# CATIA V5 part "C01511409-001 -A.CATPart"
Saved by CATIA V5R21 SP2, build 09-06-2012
Part number: C01511409-001
Revision: ---
Description: PROPRIETARY NOTICE (do not delete / modify)  ***************************************************************************************************  LA SOCIETE EN COMMANDITE  AIRBUS CANADA  ("AIRBUS CANADA")  PAR  L'INTERMEDIAIRE  DE  SES  DIVISIONS  ET/OU  FILIALES  CORPORATIVES,  FOURNIT  LES PRESENTES  INFORMATIONS  AU  GOUVERNEMENT  A  TITRE CONFIDENTIEL. CES  INFORMATIONS ONT UNE TENEUR CONFIDENTIELLE,  AVEC DROITS DE PROPRIETE,  ET NOUS LES CONSIDERONS  EXCLUS  DE   L'APPLICATION  DE  LA LOI SUR L'ACCES A L'INFORMATION  (CANADA),  LES  LOIS  SUR  L'ACCES  A  L'INFORMATION  EUROPEENNES,  LE FREEDOM OF INFORMATION ACT (ETATS-UNIS) ET D'AUTRES LOIS SEMBLABLES. ELLES  PEUVENT  AUSSI  CONSTITUER DES SECRETS INDUSTRIELS DE NOTRE SOCIETE OU DE TIERCES PARTIES. LA DIVULGATION  PUBLIQUE  DE CES  INFORMATIONS NUIRAIT A AIRBUS CANADA OU A DES TIERCES PARTIES.  CES INFORMATIONS PEUVENT EGALEMENT CONTENIR  DES DONNEES QUI SONT CONTROLEE PAR DES LOIS DE CONTROLE DES EXPORTATIONS DU CANADA, L’EUROPE OU LES  ETATS-  UNIS. TOUTE EXPORTATION OU REEXPORTATION DE DONNEES CONTROLEES SANS AUTORISATION EST STRICTEMENT INTERDITE.  TOUTE INTENTION DE LES DIVULGUER EN TOUT OU EN PARTIE DEVRA ETRE SIGNIFIEE A L'AVANCE ET PAR ECRIT AU VICE-  PRESIDENT, SERVICES JURIDIQUES ET CONFORMITE ET SECRETAIRE CORPORATIF D'AIRBUS CANADA.    AIRBUS CANADA LIMITED PARTNERSHIP  ("AIRBUS CANADA"),  BY ITS AFFILIATES AND/OR SUBSIDIARIES, PROVIDES THIS  INFORMATION TO THE GOVERNMENT IN CONFIDENCE. THIS IS PROPRIETARY CONFIDENTIAL INFORMATION WHICH WE CONSIDER  EXCLUDED  FROM  THE  APPLICATION OF THE ACCESS TO INFORMATION ACT (CANADA),  THE FREEDOM OF INFORMATION ACT  (U.S.A.),  THE ACCESS TO INFORMATION LAWS IN EUROPE, AND OTHER SIMILAR LEGISLATION. AND MAY ALSO CONSTITUTE  TRADE SECRETS OF OUR  COMPANY OR THIRD PARTIES.  PUBLIC  RELEASE  OF  THIS INFORMATION  WOULD BE HARMFUL TO  AIRBUS CANADA OR THIRD PARTIES.  THIS  INFORMATION  MAY  ALSO  CONTAIN DATA THAT IS CONTROLLED BY CANADIAN,  EUROPEAN, OR U.S.A. EXPORT CONTROL LAWS. ANY UNAUTHORIZED EXPORT OR RE-EXPORT OF ANY EXPORT CONTROLLED DATA  IS STRICTLY PROHIBITED  ANY INTENTION TO DISCLOSE SUCH INFORMATION,  OR  PART THEREOF,  MUST BE NOTIFIED IN  ADVANCE AND IN WRITING TO THE VICE PRESIDENT, LEGAL AND COMPLIANCE AND CORPORATE SECRETARY OF AIRBUS CANADA.        LES RENSEIGNEMENTS,  LES DONNEES  ET  DESSINS  TECHNIQUES  DIVULGUES  DANS  LES PRESENTES SONT LA PROPRIETE  EXCLUSIVE DE LA SOCIETE EN COMMANDITE AIRBUS CANADA ("AIRBUS CANADA") OU COMPORTENT DES DROITS DE PROPRIETE  APPARTENANT  A  AUTRUI ET NE PEUVENT ETRE DIVULGUES  A  QUICONQUE  NI  UTILISES PAR QUI QUE CE SOIT SANS LE  CONSENTEMENT  ECRIT  D’AIRBUS  CANADA.  LE DETENTEUR DES  PRESENTES  S'ENGAGE, DANS TOUTES CIRCONSTANCES, A  GARDER CONFIDENTIELS LES DONNEES ET DESSINS TECHNIQUES QU'ELLES CONTIENNENT.   CE QUI PRECEDE NE S'APPLIQUE  PAS  AUX PERSONNES  QUI  ONT DES DROITS DE PROPRIETE SUR CES RENSEIGNEMENTS,  DONNEES TECHNIQUES ET DESSINS  DANS LA MESURE OU CES DROITS EXISTENT.    THE INFORMATION,  TECHNICAL DATA  AND  DESIGNS DISCLOSED HEREIN ARE THE EXCLUSIVE PROPERTY OF AIRBUS CANADA  LIMITED PARTNERSHIP  ("AIRBUS CANADA")  OR  CONTAIN PROPRIETARY RIGHTS OF OTHERS  AND ARE NOT TO BE USED OR  DISCLOSED  TO  OTHERS WITHOUT THE WRITTEN CONSENT OF AIRBUS CANADA.  THE RECIPIENT OF THIS DOCUMENT, BY ITS  RETENTION  AND  USE  AGREES TO  HOLD  IN  CONFIDENCE  THE  TECHNICAL DATA AND DESIGNS CONTAINED HEREIN. THE  FOREGOING SHALL NOT APPLY TO PERSONS HAVING PROPRIETARY RIGHTS TO SUCH INFORMATION,  TECHNICAL DATA OR SUCH  DESIGNS TO THE EXTENT THAT SUCH RIGHTS EXIST.    Copyright 2020 Airbus Canada Limited Partnership. All Rights Reserved.  ***********************************
Property "Title": "STOPPER, GIRT BAR, PASS SVCE DR"
Property "Dataset Type": "DETAIL"
Property "MFG Process": "MACHINED"
Property "Design Authority Program": "BD-500"
Property "Supplier Name And CAGE Code": "AIRBUS CANADA LIMITED PARTNERSHIP L0J48"
Property "Major Supplier Code": "LP"
Property "3D Only": "N/A"
Property "Dimensions": "DIMENSIONS ARE IN INCHES"
Property "Color Coded": "N/A"
Property "Roughness": "ALL MACHINED SURFACES 125 Ra MAX"
Property "Eng. Tolerances": "LINEAR .XX= +/-.03; .XXX= +/-.010; ANGULAR= +/-0.5 DEG"
Property "Tool Design Tolerances": "LINEAR .X= +/-.06; .XX= +/-.015; .XXX= +/-.005; .XXXX= +/-.001; ANGULAR= +/-0.5 DEG"
Property "Material Form": "BAR - ROUND"
Property "Finish Code": "T002"
Property "Wire Gauge": "-"
Property "Form": "N/A"
Property "Type": "N/A"
Property "Style": "N/A"
Property "Density": "N/A"
Property "Material Specification Production": "AMS4928"
Property "Material Description Production": "TITANIUM"
Property "Alloy": "6AL-4V"
Property "Material Class": "N/A"
Property "Grade/Composition": "N/A"
Property "Final Condition": "ANL"
Property "Standard Spec Die": "N/A"
Property "Mesh Cell Size": "N/A"
Property "PCCN": "2"
Property "Organization": "DESIGN"
Property "Length": 0
Property "Width": 0
Property "Inside Diameter": 0
Property "Outside Diameter": 1.5
Property "Wall": 0
Property "Thickness": 0
Property "Project": "BA"
Publications: "PartBody", "Extract_Datum_A", "Extract_Datum_B", "Extract_Datum_C", "REFERENCE PLANE"
Material "TI-6AL-4V": density 4428.78 kg/m3, Young's modulus 1.11695e+11 Pa, Poisson ratio 0.31
Bounding box of the stored display mesh (mm): x -15.24 to 15.24, y -15.24 to 15.24, z 0 to 66.989
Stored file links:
  C:\Users\CQQZ006\Desktop\A220钢钛件\舱门\C01511409-001\C01511409-001 -A.CATPart

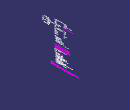
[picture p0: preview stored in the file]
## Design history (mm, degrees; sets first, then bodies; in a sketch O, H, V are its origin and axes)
AxisSystem1: origin (0, 0, 0), X (1, 0, 0), Y (0, 1, 0), Z (0, 0, 1)
TTRSSet1
Part_3D_Annotations1 "CATTPSSet"
Set1 "Pilot_Holes"
  Set2 "3/16"
    Point1 "Fix Point": (0, 0, 0), relative to Sketch1, in AxisSystem1
    Line1 "Fix Orientation": type PtDir, RefPoint Point1, Direction Plane3, Start -25.3568, End 6.35
Set3 "References"
  Plane1 "REFERENCE PLANE": type Offset, RefPlane face of Shaft1 from Sketch2.L2, Offset 0, reversed
Set4 "Geometrical Set for 3D Annotations"
  Set5 "No Show Geometry"
    Extract1 "Extract_Datum_A": ExtractElem face of Shaft1 from Sketch2.L5
    Extract2 "Extract_Datum_B": ExtractElem face of Shaft1 from Sketch2.L4
    Extract3 "Extract_Datum_C": ExtractElem face of Pocket2 from Sketch4.A2
Set6 "Construction_Geometry"
  Set7 "Sketches_Not_Used_By_PartBody"
    Sketch1 on Plane2, origin (0, 0, 59.7497), H (1, 0, 0), V (0, 1, 0)
      construction line L1 (0, 0) -> (6.7199, 6.7199)
      point P1 (6.7199, 6.7199)
      reference projected circle E1 centre (0, 0) radius 9.5034 from edge [face of Shaft1 from Sketch2.L5 | face of Chamfer1]
      angle L1 H = 45
      coincidence: E1 P1
  Plane2: type Offset, RefPlane xy-plane, Offset 59.7497
  Point2: (0, 0, 0), in AxisSystem1
  Line2: type PtDir, RefPoint Point2, Direction xy-plane, Start 0, End 25.4
  Plane3: type Angle, RefPlane yz-plane, Direction Line2, Angle 45
Body1 (main body)
  Sketch2 on ZX plane of AxisSystem1, origin (0, 0, 0), H (0, 0, 1), V (1, 0, 0)
    line L1 (66.9887, 7.9794) -> (0, 7.9794)
    line L2 (0, 7.9794) -> (0, 15.24)
    line L3 (0, 15.24) -> (1.524, 15.24)
    line L4 (1.524, 15.24) -> (1.524, 9.8844)
    line L5 (1.905, 9.5034) -> (66.9887, 9.5034)
    line L6 (66.9887, 9.5034) -> (66.9887, 7.9794)
    arc A1 centre (1.905, 9.8844) radius 0.381 from (1.524, 9.8844) to (1.905, 9.5034) ccw
    reference intersected line E1 through (59.7497, 0) direction (0, 1) from Plane2
    distance L2 L4 = 1.524
    distance L5 L1 = 1.524
    distance H L5 = 9.5034
    radius A1 = 0.381
    distance H L3 = 15.24
    distance E1 L6 = 7.239
    coincidence: L2 V
    tangency: A1 L4, A1 L5
  Shaft1: profile Sketch2, axis edge [ZX plane of AxisSystem1 | YZ plane of AxisSystem1], angle 360
  Sketch3 on zx-plane, origin (0, 0, 0), H (0, 0, 1), V (-1, 0, 0)
    construction line L1 (8.89, 0) -> (48.7007, 0)
    line L2 (8.89, 3.81) -> (48.7007, 3.81)
    line L3 (48.7007, -3.81) -> (8.89, -3.81)
    arc A1 centre (48.7007, 0) radius 3.81 from (48.7007, 3.81) to (48.7007, -3.81) cw
    arc A2 centre (8.89, 0) radius 3.81 from (8.89, -3.81) to (8.89, 3.81) cw
    reference intersected line E1 through (0, 0) direction (0, 1) from face of Shaft1 from Sketch2.L2
    reference intersected line E2 through (66.9887, 0) direction (0, 1) from face of Shaft1 from Sketch2.L6
    distance L1 L2 = 3.81
    distance E1 A2 = 5.08
    distance E2 A1 = 14.478
    horizontal: L1 H
    tangency: A1 L2, A2 L2, A1 L3, A2 L3
    coincidence: L1 H
  Pocket1: profile Sketch3, direction (0, 1, 0), through (limit type 3), opposite side through (limit type 3)
  Sketch4 on yz-plane, origin (0, 0, 0), H (0, 0, 1), V (0, 1, 0)
    construction line L1 (8.89, 0) -> (48.7007, 0)
    line L2 (8.89, 3.81) -> (48.7007, 3.81)
    line L3 (48.7007, -3.81) -> (8.89, -3.81)
    arc A1 centre (48.7007, 0) radius 3.81 from (48.7007, 3.81) to (48.7007, -3.81) cw
    arc A2 centre (8.89, 0) radius 3.81 from (8.89, -3.81) to (8.89, 3.81) cw
    reference intersected line E1 through (0, 0) direction (0, 1) from face of Shaft1 from Sketch2.L2
    reference intersected line E2 through (66.9887, 0) direction (0, 1) from face of Shaft1 from Sketch2.L6
    distance L1 L2 = 3.81
    distance E1 A2 = 5.08
    distance E2 A1 = 14.478
    horizontal: L1 H
    tangency: A1 L2, A2 L2, A1 L3, A2 L3
    coincidence: L1 H
  Pocket2: profile Sketch4, direction (1, 0, 0), through (limit type 3), opposite side through (limit type 3)
  Chamfer1: length 1.016, angle 45, on edge [face of Shaft1 from Sketch2.L5 | face of Shaft1 from Sketch2.L6]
